One B-rep face of a CAD part: STEP entity #137.
In plain terms, the planar face has unit normal (0, -1, 0).
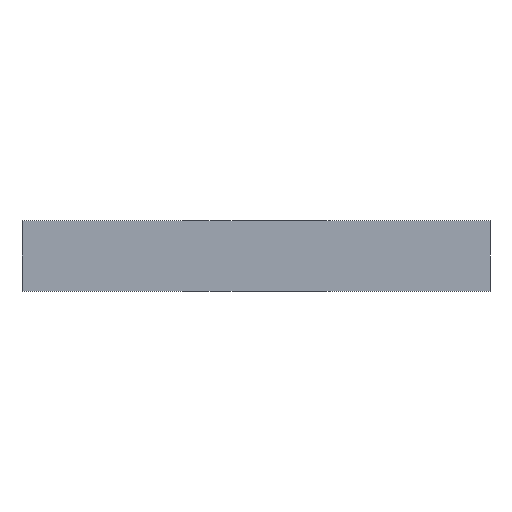
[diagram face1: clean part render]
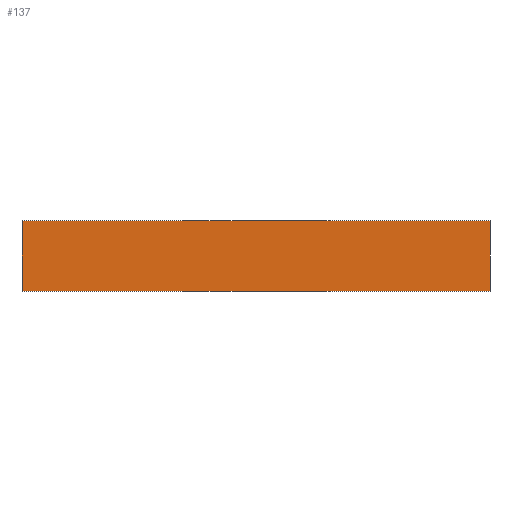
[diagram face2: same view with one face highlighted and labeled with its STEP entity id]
Its self-contained STEP definition (entity closure, numbers rounded to 3 decimals):
#21 = EDGE_CURVE('',#22,#24,#26,.T.);
#22 = VERTEX_POINT('',#23);
#23 = CARTESIAN_POINT('',(24.,0.,0.));
#24 = VERTEX_POINT('',#25);
#25 = CARTESIAN_POINT('',(24.,0.,1.2));
#26 = SURFACE_CURVE('',#27,(#31,#43),.PCURVE_S1.);
#27 = LINE('',#28,#29);
#28 = CARTESIAN_POINT('',(24.,0.,0.));
#29 = VECTOR('',#30,1.);
#30 = DIRECTION('',(0.,0.,1.));
#31 = PCURVE('',#32,#37);
#32 = PLANE('',#33);
#33 = AXIS2_PLACEMENT_3D('',#34,#35,#36);
#34 = CARTESIAN_POINT('',(24.,0.,0.));
#35 = DIRECTION('',(1.,0.,-0.));
#36 = DIRECTION('',(0.,0.,1.));
#37 = DEFINITIONAL_REPRESENTATION('',(#38),#42);
#38 = LINE('',#39,#40);
#39 = CARTESIAN_POINT('',(0.,0.));
#40 = VECTOR('',#41,1.);
#41 = DIRECTION('',(1.,0.));
#42 = ( GEOMETRIC_REPRESENTATION_CONTEXT(2) 
PARAMETRIC_REPRESENTATION_CONTEXT() REPRESENTATION_CONTEXT('2D SPACE',''
  ) );
#43 = PCURVE('',#44,#49);
#44 = PLANE('',#45);
#45 = AXIS2_PLACEMENT_3D('',#46,#47,#48);
#46 = CARTESIAN_POINT('',(24.,0.,0.));
#47 = DIRECTION('',(-0.,1.,0.));
#48 = DIRECTION('',(0.,0.,1.));
#49 = DEFINITIONAL_REPRESENTATION('',(#50),#54);
#50 = LINE('',#51,#52);
#51 = CARTESIAN_POINT('',(0.,0.));
#52 = VECTOR('',#53,1.);
#53 = DIRECTION('',(1.,0.));
#54 = ( GEOMETRIC_REPRESENTATION_CONTEXT(2) 
PARAMETRIC_REPRESENTATION_CONTEXT() REPRESENTATION_CONTEXT('2D SPACE',''
  ) );
#72 = PLANE('',#73);
#73 = AXIS2_PLACEMENT_3D('',#74,#75,#76);
#74 = CARTESIAN_POINT('',(24.,0.,0.));
#75 = DIRECTION('',(0.,0.,1.));
#76 = DIRECTION('',(1.,0.,-0.));
#126 = PLANE('',#127);
#127 = AXIS2_PLACEMENT_3D('',#128,#129,#130);
#128 = CARTESIAN_POINT('',(24.,0.,1.2));
#129 = DIRECTION('',(0.,0.,1.));
#130 = DIRECTION('',(1.,0.,-0.));
#137 = ADVANCED_FACE('',(#138),#44,.F.);
#138 = FACE_BOUND('',#139,.F.);
#139 = EDGE_LOOP('',(#140,#163,#164,#187));
#140 = ORIENTED_EDGE('',*,*,#141,.F.);
#141 = EDGE_CURVE('',#22,#142,#144,.T.);
#142 = VERTEX_POINT('',#143);
#143 = CARTESIAN_POINT('',(32.,0.,0.));
#144 = SURFACE_CURVE('',#145,(#149,#156),.PCURVE_S1.);
#145 = LINE('',#146,#147);
#146 = CARTESIAN_POINT('',(24.,0.,0.));
#147 = VECTOR('',#148,1.);
#148 = DIRECTION('',(1.,0.,-0.));
#149 = PCURVE('',#44,#150);
#150 = DEFINITIONAL_REPRESENTATION('',(#151),#155);
#151 = LINE('',#152,#153);
#152 = CARTESIAN_POINT('',(0.,0.));
#153 = VECTOR('',#154,1.);
#154 = DIRECTION('',(0.,1.));
#155 = ( GEOMETRIC_REPRESENTATION_CONTEXT(2) 
PARAMETRIC_REPRESENTATION_CONTEXT() REPRESENTATION_CONTEXT('2D SPACE',''
  ) );
#156 = PCURVE('',#72,#157);
#157 = DEFINITIONAL_REPRESENTATION('',(#158),#162);
#158 = LINE('',#159,#160);
#159 = CARTESIAN_POINT('',(0.,0.));
#160 = VECTOR('',#161,1.);
#161 = DIRECTION('',(1.,0.));
#162 = ( GEOMETRIC_REPRESENTATION_CONTEXT(2) 
PARAMETRIC_REPRESENTATION_CONTEXT() REPRESENTATION_CONTEXT('2D SPACE',''
  ) );
#163 = ORIENTED_EDGE('',*,*,#21,.T.);
#164 = ORIENTED_EDGE('',*,*,#165,.T.);
#165 = EDGE_CURVE('',#24,#166,#168,.T.);
#166 = VERTEX_POINT('',#167);
#167 = CARTESIAN_POINT('',(32.,0.,1.2));
#168 = SURFACE_CURVE('',#169,(#173,#180),.PCURVE_S1.);
#169 = LINE('',#170,#171);
#170 = CARTESIAN_POINT('',(24.,0.,1.2));
#171 = VECTOR('',#172,1.);
#172 = DIRECTION('',(1.,0.,-0.));
#173 = PCURVE('',#44,#174);
#174 = DEFINITIONAL_REPRESENTATION('',(#175),#179);
#175 = LINE('',#176,#177);
#176 = CARTESIAN_POINT('',(1.2,0.));
#177 = VECTOR('',#178,1.);
#178 = DIRECTION('',(0.,1.));
#179 = ( GEOMETRIC_REPRESENTATION_CONTEXT(2) 
PARAMETRIC_REPRESENTATION_CONTEXT() REPRESENTATION_CONTEXT('2D SPACE',''
  ) );
#180 = PCURVE('',#126,#181);
#181 = DEFINITIONAL_REPRESENTATION('',(#182),#186);
#182 = LINE('',#183,#184);
#183 = CARTESIAN_POINT('',(0.,0.));
#184 = VECTOR('',#185,1.);
#185 = DIRECTION('',(1.,0.));
#186 = ( GEOMETRIC_REPRESENTATION_CONTEXT(2) 
PARAMETRIC_REPRESENTATION_CONTEXT() REPRESENTATION_CONTEXT('2D SPACE',''
  ) );
#187 = ORIENTED_EDGE('',*,*,#188,.F.);
#188 = EDGE_CURVE('',#142,#166,#189,.T.);
#189 = SURFACE_CURVE('',#190,(#194,#201),.PCURVE_S1.);
#190 = LINE('',#191,#192);
#191 = CARTESIAN_POINT('',(32.,0.,0.));
#192 = VECTOR('',#193,1.);
#193 = DIRECTION('',(0.,0.,1.));
#194 = PCURVE('',#44,#195);
#195 = DEFINITIONAL_REPRESENTATION('',(#196),#200);
#196 = LINE('',#197,#198);
#197 = CARTESIAN_POINT('',(0.,8.));
#198 = VECTOR('',#199,1.);
#199 = DIRECTION('',(1.,0.));
#200 = ( GEOMETRIC_REPRESENTATION_CONTEXT(2) 
PARAMETRIC_REPRESENTATION_CONTEXT() REPRESENTATION_CONTEXT('2D SPACE',''
  ) );
#201 = PCURVE('',#202,#207);
#202 = PLANE('',#203);
#203 = AXIS2_PLACEMENT_3D('',#204,#205,#206);
#204 = CARTESIAN_POINT('',(32.,0.,0.));
#205 = DIRECTION('',(1.,0.,-0.));
#206 = DIRECTION('',(0.,0.,1.));
#207 = DEFINITIONAL_REPRESENTATION('',(#208),#212);
#208 = LINE('',#209,#210);
#209 = CARTESIAN_POINT('',(0.,0.));
#210 = VECTOR('',#211,1.);
#211 = DIRECTION('',(1.,0.));
#212 = ( GEOMETRIC_REPRESENTATION_CONTEXT(2) 
PARAMETRIC_REPRESENTATION_CONTEXT() REPRESENTATION_CONTEXT('2D SPACE',''
  ) );
